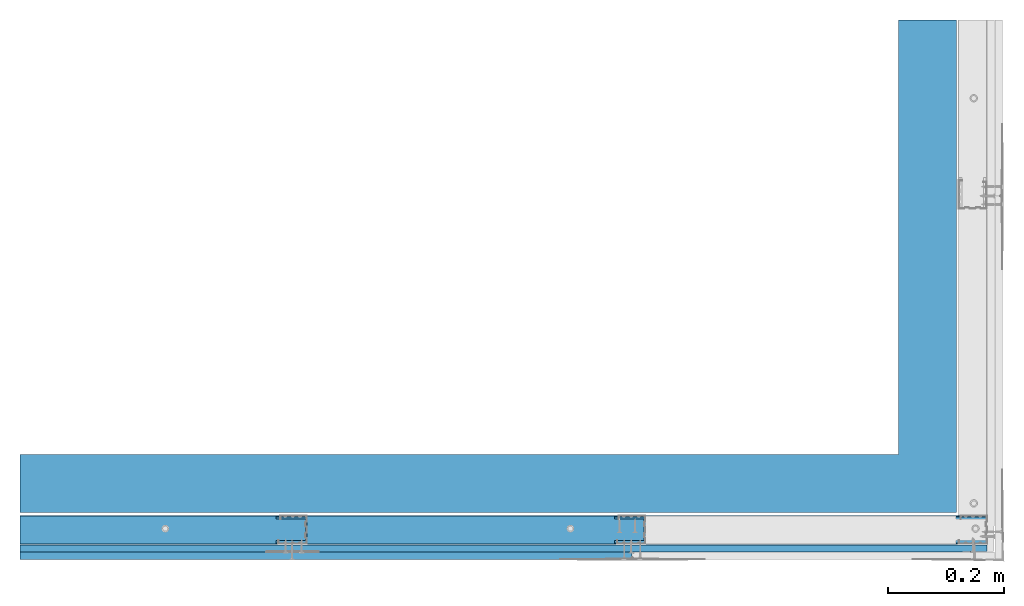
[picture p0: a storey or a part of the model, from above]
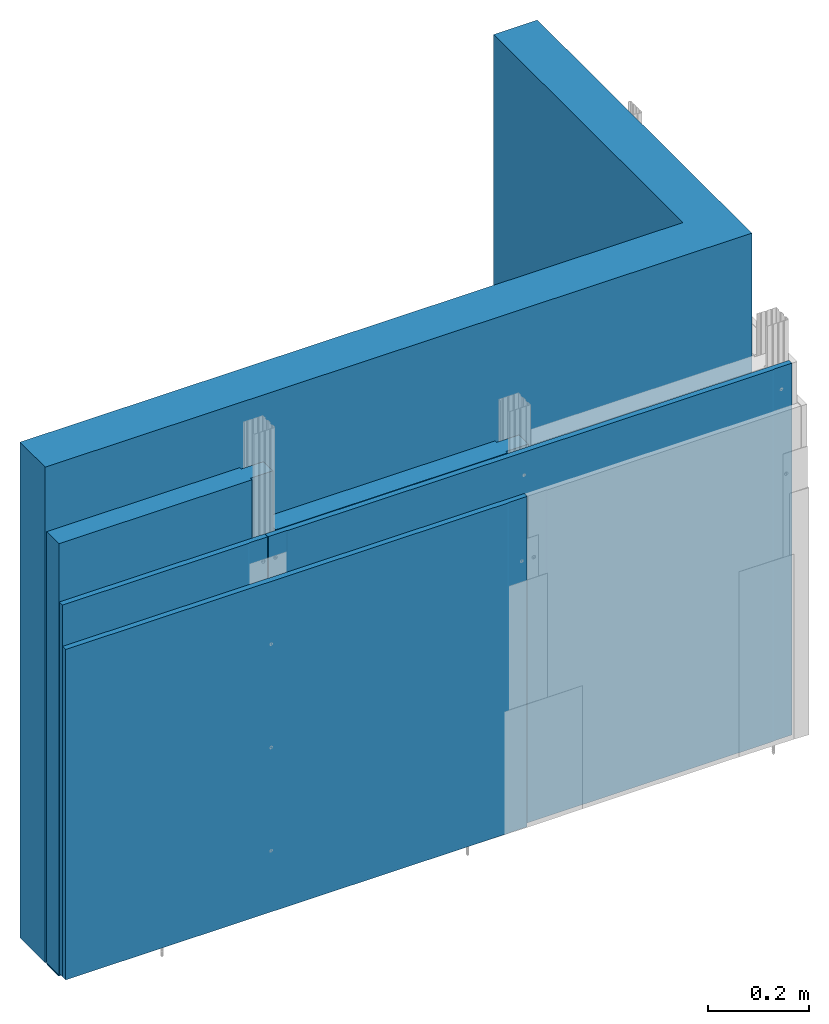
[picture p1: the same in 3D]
Properties of the parts of a building model (IFC2X3)

# File
Description: ViewDefinition [CoordinationView]
Time: 2022-01-05T15:37:04
Made in: SketchUp Pro 2015

# IfcProject, Default Project
Description: Description of Default Project

# IfcSite, Default Site
Description: Description of Default Site; RefLatitude: 24, 28, 0; RefLongitude: 54, 25, 0; RefElevation: 10 mm

# IfcBuilding, Default Building
Description: Description of Default Building

# IfcBuildingStorey, Default Building Storey
In: Default Building
Description: Description of Default Building Storey; Elevation: 0 mm

# IfcWall (77)
In: Default Building Storey
Description: Description of Object
Name
14 x Wkręt RIGIPS TN 25
4 x Dedykowana masa szpachlowa Rigips - konstrukcyjna
4 x Dedykowana masa szpachlowa Rigips - wykończeniowa
2 x Taśma spoinowa RIGIPS
4 x Profil RIGIPS CW50 ULTRASTIL®
5 x Wełna mineralna szklana lub skalna
2 x Profil RIGIPS UW50 ULTRASTIL®
2 x Taśma uszczelniająca piankowa RIGIPS
ŚCIANA
7 x Płyta gipsowo-kartonowa RIGIPS PRO (4PRO™)
Taśma narożnikowa HABITO® NO-COAT® | dynamic_attributes - _has_movetool_behaviors: 0; _lengthunits: CENTIMETERS; _name: Taśma narożnikowa HABITO® NOCOAT®; _formatversion: 1; _lastmodified: 2021-12-02 11:34; IfcPropertySet - _last_lenx: 01.69291; _last_leny: 01.692911.69291; _last_lenz: 01.692911.6929123.5571
21 x Wkręt RIGIPS TN 35
10 x Kołek rozporowy min. fi 6
